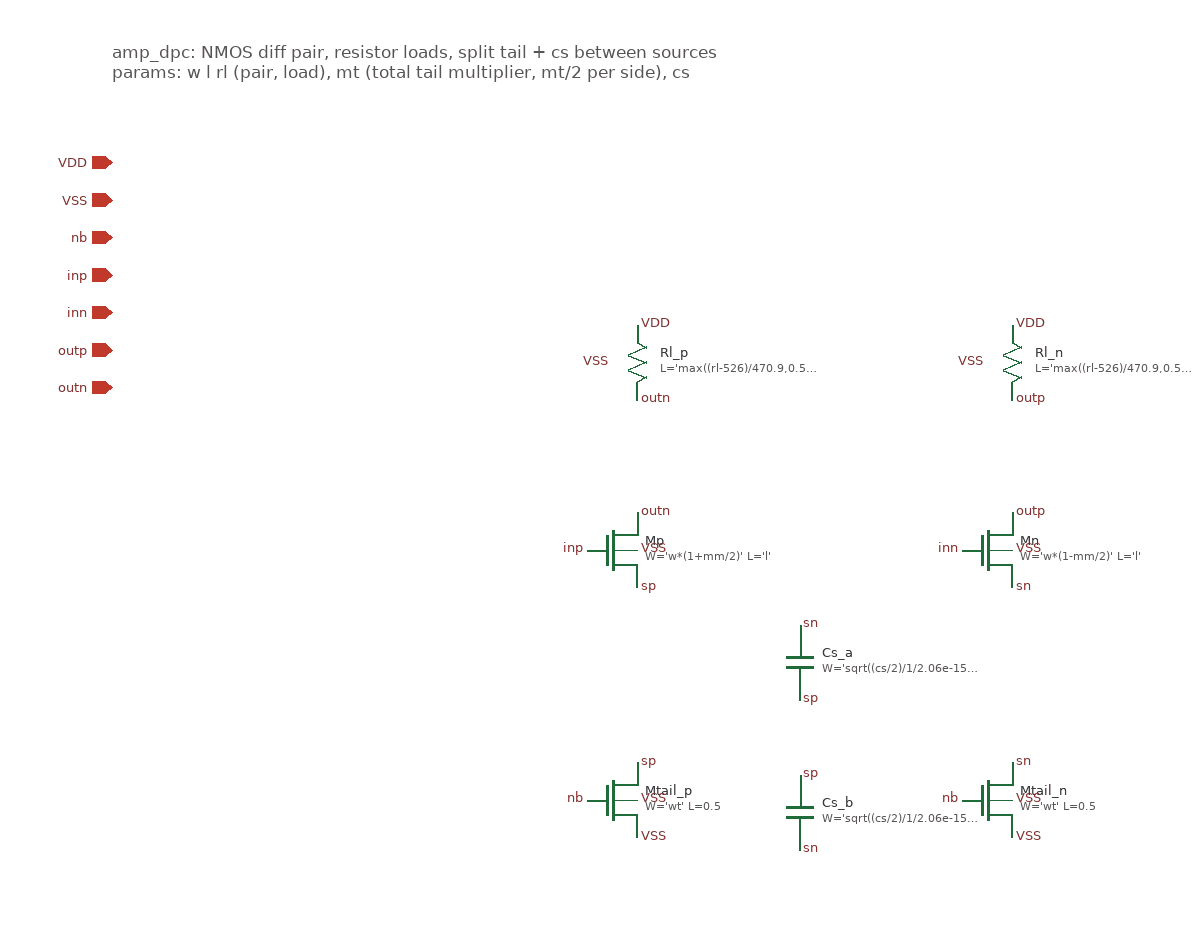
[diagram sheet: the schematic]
v {xschem version=3.4.5 file_version=1.2
}
G {}
K {}
V {}
S {}
E {}
T {amp_dpc: NMOS diff pair, resistor loads, split tail + cs between sources
params: w l rl (pair, load), mt (total tail multiplier, mt/2 per side), cs} -400 -560 0 0 0.4 0.4 {}
C {devices/iopin.sym} -400 -460 0 0 {name=p1
lab=VDD}
C {devices/iopin.sym} -400 -430 0 0 {name=p2
lab=VSS}
C {devices/iopin.sym} -400 -400 0 0 {name=p3
lab=nb}
C {devices/iopin.sym} -400 -370 0 0 {name=p4
lab=inp}
C {devices/iopin.sym} -400 -340 0 0 {name=p5
lab=inn}
C {devices/iopin.sym} -400 -310 0 0 {name=p6
lab=outp}
C {devices/iopin.sym} -400 -280 0 0 {name=p7
lab=outn}
C {sky130_fd_pr/res_high_po_0p69.sym} 20 -300 0 0 {name=Rl_p
L='max((rl-526)/470.9,0.5)'
model=res_high_po_0p69
mult=1
spiceprefix=X}
C {devices/lab_pin.sym} 20 -330 0 1 {name=p8
sig_type=std_logic
lab=VDD}
C {devices/lab_pin.sym} 20 -270 0 1 {name=p9
sig_type=std_logic
lab=outn}
C {devices/lab_pin.sym} 0 -300 0 0 {name=p10
sig_type=std_logic
lab=VSS}
C {sky130_fd_pr/nfet_01v8.sym} 0 -150 0 0 {name=Mp
nf=4
mult=1
ad="'int((nf+1)/2) * W/nf * 0.29'"
pd="'2*int((nf+1)/2) * (W/nf + 0.29)'"
as="'int((nf+2)/2) * W/nf * 0.29'"
ps="'2*int((nf+2)/2) * (W/nf + 0.29)'"
nrd="'0.29 / W'"
nrs="'0.29 / W'"
sa=0
sb=0
sd=0
L='l'
W='w*(1+mm/2)'
model=nfet_01v8
spiceprefix=X}
C {devices/lab_pin.sym} 20 -180 0 1 {name=p11
sig_type=std_logic
lab=outn}
C {devices/lab_pin.sym} -20 -150 0 0 {name=p12
sig_type=std_logic
lab=inp}
C {devices/lab_pin.sym} 20 -120 0 1 {name=p13
sig_type=std_logic
lab=sp}
C {devices/lab_pin.sym} 20 -150 0 1 {name=p14
sig_type=std_logic
lab=VSS}
C {sky130_fd_pr/nfet_01v8.sym} 0 50 0 0 {name=Mtail_p
nf=2
mult='mt/2'
ad="'int((nf+1)/2) * W/nf * 0.29'"
pd="'2*int((nf+1)/2) * (W/nf + 0.29)'"
as="'int((nf+2)/2) * W/nf * 0.29'"
ps="'2*int((nf+2)/2) * (W/nf + 0.29)'"
nrd="'0.29 / W'"
nrs="'0.29 / W'"
sa=0
sb=0
sd=0
L=0.5
W='wt'
model=nfet_01v8
spiceprefix=X}
C {devices/lab_pin.sym} 20 20 0 1 {name=p15
sig_type=std_logic
lab=sp}
C {devices/lab_pin.sym} -20 50 0 0 {name=p16
sig_type=std_logic
lab=nb}
C {devices/lab_pin.sym} 20 80 0 1 {name=p17
sig_type=std_logic
lab=VSS}
C {devices/lab_pin.sym} 20 50 0 1 {name=p18
sig_type=std_logic
lab=VSS}
C {sky130_fd_pr/res_high_po_0p69.sym} 320 -300 0 0 {name=Rl_n
L='max((rl-526)/470.9,0.5)'
model=res_high_po_0p69
mult=1
spiceprefix=X}
C {devices/lab_pin.sym} 320 -330 0 1 {name=p19
sig_type=std_logic
lab=VDD}
C {devices/lab_pin.sym} 320 -270 0 1 {name=p20
sig_type=std_logic
lab=outp}
C {devices/lab_pin.sym} 300 -300 0 0 {name=p21
sig_type=std_logic
lab=VSS}
C {sky130_fd_pr/nfet_01v8.sym} 300 -150 0 0 {name=Mn
nf=4
mult=1
ad="'int((nf+1)/2) * W/nf * 0.29'"
pd="'2*int((nf+1)/2) * (W/nf + 0.29)'"
as="'int((nf+2)/2) * W/nf * 0.29'"
ps="'2*int((nf+2)/2) * (W/nf + 0.29)'"
nrd="'0.29 / W'"
nrs="'0.29 / W'"
sa=0
sb=0
sd=0
L='l'
W='w*(1-mm/2)'
model=nfet_01v8
spiceprefix=X}
C {devices/lab_pin.sym} 320 -180 0 1 {name=p22
sig_type=std_logic
lab=outp}
C {devices/lab_pin.sym} 280 -150 0 0 {name=p23
sig_type=std_logic
lab=inn}
C {devices/lab_pin.sym} 320 -120 0 1 {name=p24
sig_type=std_logic
lab=sn}
C {devices/lab_pin.sym} 320 -150 0 1 {name=p25
sig_type=std_logic
lab=VSS}
C {sky130_fd_pr/nfet_01v8.sym} 300 50 0 0 {name=Mtail_n
nf=2
mult='mt/2'
ad="'int((nf+1)/2) * W/nf * 0.29'"
pd="'2*int((nf+1)/2) * (W/nf + 0.29)'"
as="'int((nf+2)/2) * W/nf * 0.29'"
ps="'2*int((nf+2)/2) * (W/nf + 0.29)'"
nrd="'0.29 / W'"
nrs="'0.29 / W'"
sa=0
sb=0
sd=0
L=0.5
W='wt'
model=nfet_01v8
spiceprefix=X}
C {devices/lab_pin.sym} 320 20 0 1 {name=p26
sig_type=std_logic
lab=sn}
C {devices/lab_pin.sym} 280 50 0 0 {name=p27
sig_type=std_logic
lab=nb}
C {devices/lab_pin.sym} 320 80 0 1 {name=p28
sig_type=std_logic
lab=VSS}
C {devices/lab_pin.sym} 320 50 0 1 {name=p29
sig_type=std_logic
lab=VSS}
C {sky130_fd_pr/cap_mim_m3_1.sym} 150 -60 0 0 {name=Cs_a
model=cap_mim_m3_1
W='sqrt((cs/2)/1/2.06e-15)'
L='sqrt((cs/2)/1/2.06e-15)'
MF=1
spiceprefix=X}
C {devices/lab_pin.sym} 150 -90 0 1 {name=p30
sig_type=std_logic
lab=sn}
C {devices/lab_pin.sym} 150 -30 0 1 {name=p31
sig_type=std_logic
lab=sp}
C {sky130_fd_pr/cap_mim_m3_1.sym} 150 60 0 0 {name=Cs_b
model=cap_mim_m3_1
W='sqrt((cs/2)/1/2.06e-15)'
L='sqrt((cs/2)/1/2.06e-15)'
MF=1
spiceprefix=X}
C {devices/lab_pin.sym} 150 30 0 1 {name=p32
sig_type=std_logic
lab=sp}
C {devices/lab_pin.sym} 150 90 0 1 {name=p33
sig_type=std_logic
lab=sn}
